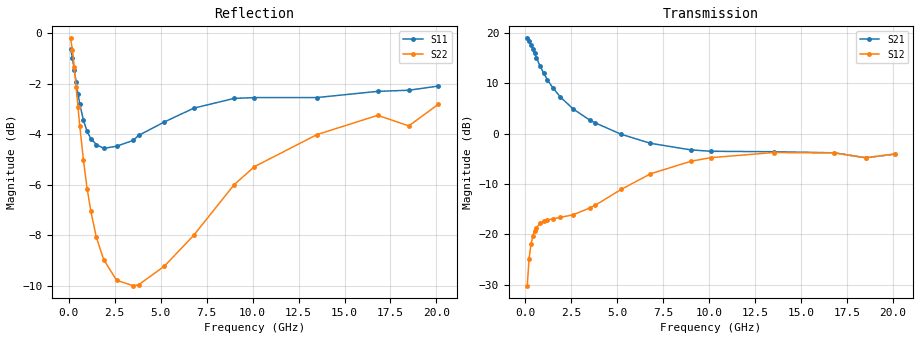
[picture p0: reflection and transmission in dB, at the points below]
!  Infineon Technologies AG
! BFR380L3 , PF131585-7, No.6, Th 09.10.01, soldered on pcb-board, measured with PP GSG850
!  Vce=2.5 V,  Ic=2.5 mA
! Common Emitter S-Parameters:  15. November 2001
#  GHz  S  MA  R  50
! f  S11  S21  S12  S22
! GHz  Mag  Ang  Mag  Ang  Mag  Ang  Mag  Ang
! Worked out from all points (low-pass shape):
!   201 points, 100 MHz to 20.1 GHz, reference 50 ohm
!   highest |S21| = 18.89 dB at 100 MHz (marker M1); lowest = -4.8 dB at 18.5 GHz (marker M2)
!   |S21| within 3 dB of the highest: start of sweep to 501.9 MHz
!   lowest |S11| = -4.6 dB at 1.9 GHz (marker M3), VSWR 3.90, Z = 12.9 - j4.72 ohm
!   |S11| at or under -10 dB: nowhere
!   |S22| runs from -10.0 to -0.2 dB; largest |S21 - S12| = 8.8
!   S11 on the Smith chart (normalised r, x): 100 MHz: 1.14, -5.48; 500 MHz: 0.30, -1.08; 1.2 GHz: 0.27, -0.34; 3.8 GHz: 0.25, +0.27; 9 GHz: 0.32, +1.05; 20.1 GHz: 1.00, +2.55
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0.1  0.9317 -19.9  8.796 166.5  0.03102 79.1  0.9778 -10.8
0.2  0.8948 -38.0  8.209 154.3  0.05736 68.7  0.9277 -20.7
0.3  0.8476 -55.5  7.584 143.2  0.07948 60.1  0.8577 -29.1
0.4  0.8022 -70.0  6.896 133.7  0.09584 53.2  0.7842 -36.1
0.5  0.7594 -83.3  6.239 125.5  0.1081 47.7  0.7163 -41.6
0.6  0.7245 -94.6  5.638 118.7  0.117 43.4  0.6561 -46.0
0.8  0.6728 -113.2  4.671 107.5  0.1285 37.4  0.5602 -52.5
1  0.6392 -127.8  3.953 98.8  0.1349 33.6  0.4923 -57.0
1.2  0.6189 -139.8  3.409 91.6  0.1393 31.6  0.4444 -60.6
1.5  0.602 -153.7  2.831 82.6  0.1432 30.4  0.3946 -65.0
1.9  0.5917 -168.5  2.305 72.6  0.1475 31.2  0.356 -70.5
2.6  0.5975 172.3  1.754 58.3  0.1567 35.8  0.3239 -81.2
3.5  0.6133 153.3  1.361 43.4  0.183 43.4  0.316 -96.7
3.8  0.6276 148.0  1.276 39.3  0.1947 45.3  0.3173 -103.1
5.2  0.6675 126.3  0.9862 22.5  0.279 47.5  0.3454 -131.5
6.8  0.7108 105.4  0.8009 10.0  0.3987 40.7  0.3979 -165.5
8.999999  0.7434 84.6  0.6893 0.1  0.5318 24.2  0.5014 157.2
10.1  0.746 76.1  0.6676 -4.0  0.5776 15.5  0.5442 140.8
13.5  0.7462 58.2  0.6611 -17.8  0.6486 -8.6  0.63 103.6
16.8  0.7676 46.9  0.6446 -30.1  0.643 -25.6  0.6879 79.1
18.5  0.7716 45.3  0.5762 -38.1  0.576 -34.2  0.6556 72.9
20.1  0.7864 38.1  0.6256 -41.8  0.6284 -39.3  0.7236 61.7
